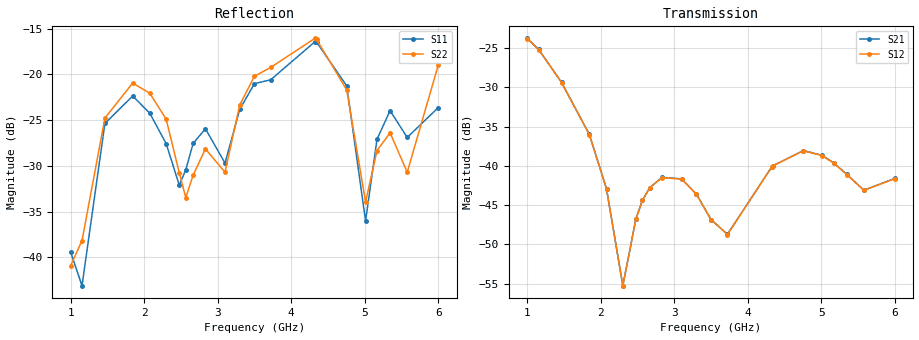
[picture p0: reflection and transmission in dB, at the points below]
!Agilent Technologies,E8364B,MY43040528,A.07.50.67
!Agilent E8364B: A.07.50.67
!Date: Sunday, March 01, 2026 20:54:35
!Correction: S11(Full 2 Port(1,2))
!S21(Full 2 Port(1,2))
!S12(Full 2 Port(1,2))
!S22(Full 2 Port(1,2))
!S2P File: Measurements: S11, S21, S12, S22:
# Hz S  dB  R 50
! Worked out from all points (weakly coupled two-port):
!   451 points, 1 GHz to 6 GHz, reference 50 ohm
!   highest |S21| = -23.75 dB at 1 GHz (marker M1); lowest = -55.3 dB at 2.3 GHz (marker M2)
!   lowest |S11| = -43.1 dB at 1.156 GHz (marker M3), VSWR 1.01, Z = 49.5 + j0.531 ohm
!   |S11| at or under -10 dB: start of sweep to end of sweep
!   |S22| runs from -41.8 to -15.8 dB; largest |S21 - S12| = 0.0002
!   S11 on the Smith chart (normalised r, x): 1 GHz: 1.01, +0.02; 4.322 GHz: 1.24, -0.24; 6 GHz: 0.99, -0.13
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1e9  -39.39 64.5  -23.75 148.7  -23.77 148.7  -40.92 32.0
1.155556e9  -43.09 130.1  -25.16 58.9  -25.18 58.9  -38.16 75.0
1.466667e9  -25.36 161.8  -29.36 -117.1  -29.38 -117.2  -24.78 83.3
1.844444e9  -22.36 93.8  -35.98 38.3  -36.00 38.3  -20.94 -3.3
2.077778e9  -24.25 66.8  -42.90 -84.7  -42.93 -84.7  -22.06 -46.3
2.3e9  -27.57 48.7  -55.25 -132.0  -55.23 -131.6  -24.90 -85.3
2.477778e9  -32.10 65.2  -46.72 -166.5  -46.78 -166.4  -30.75 -102.2
2.566667e9  -30.42 84.2  -44.36 149.0  -44.38 149.1  -33.46 -84.7
2.666667e9  -27.54 83.0  -42.75 96.3  -42.77 96.3  -31.02 -64.9
2.833333e9  -25.94 61.8  -41.45 6.5  -41.48 6.5  -28.14 -84.4
3.1e9  -29.69 67.6  -41.65 -138.4  -41.68 -138.4  -30.69 -76.4
3.3e9  -23.82 76.4  -43.58 116.4  -43.62 116.4  -23.34 -82.8
3.5e9  -21.01 50.5  -46.84 23.1  -46.84 23.1  -20.20 -119.8
3.722222e9  -20.58 31.4  -48.70 -52.5  -48.74 -52.7  -19.23 -152.0
4.322222e9  -16.43 -38.7  -40.15 25.3  -40.18 25.3  -16.06 105.0
4.344444e9  -16.46 -42.2  -39.95 13.2  -39.98 13.2  -16.17 100.2
4.755556e9  -21.26 -110.1  -38.04 139.4  -38.07 139.5  -21.71 13.8
5.011111e9  -36.02 -91.6  -38.65 -12.2  -38.68 -12.2  -33.95 16.2
5.166667e9  -27.09 -49.6  -39.61 -106.5  -39.64 -106.4  -28.33 43.4
5.344444e9  -23.96 -77.4  -41.06 141.9  -41.09 141.9  -26.38 12.0
5.577778e9  -26.89 -99.7  -43.09 -17.0  -43.11 -17.0  -30.69 17.8
6e9  -23.62 -90.6  -41.58 42.2  -41.61 42.1  -18.98 -20.7
